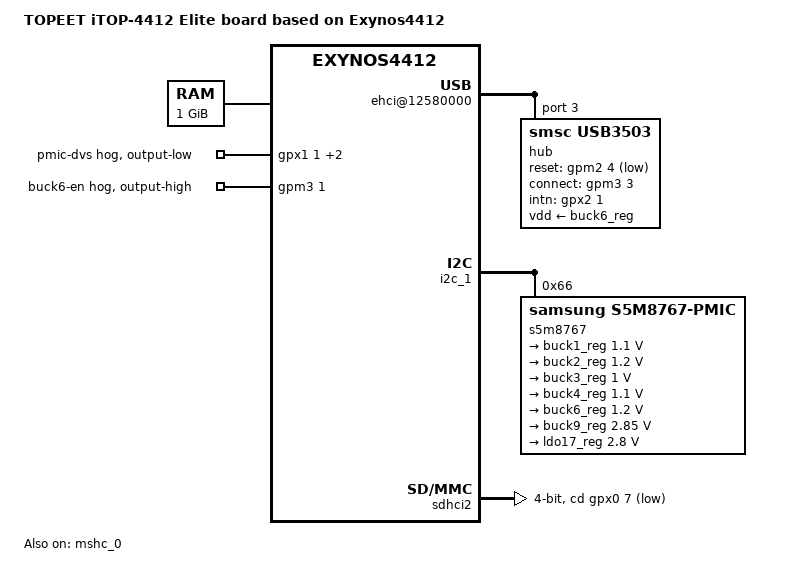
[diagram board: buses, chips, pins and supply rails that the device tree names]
/*
 * TOPEET's Exynos4412 based itop board device tree source
 *
 * Copyright (c) 2018 Samsung Electronics Co., Ltd.
 *		http://www.samsung.com
 *
 * SPDX-License-Identifier:	GPL-2.0+
 */

/dts-v1/;
#include <dt-bindings/gpio/gpio.h>
#include "skeleton.dtsi"
#include "exynos4412.dtsi"

/ {
	model = "TOPEET iTOP-4412 Elite board based on Exynos4412";
	compatible = "topeet,itop4412-elite", "samsung,exynos4412";

	chosen {
		bootargs ="console=ttySAC2,115200n8 androidboot.console=ttySAC2 ctp=1 skipcali=y";
	};

	config {
		bootcmd = "mmc rescan; mmc dev ${mmcbootdev}; \
			mmc read ${kernelloadaddr} ${kernelboff} ${kernelbsize}; \
			mmc read ${ramdiskloadaddr} ${ramdiskboff} ${ramdiskbsize}; \
			setenv initrd_high 0xffffffff; \
			bootz ${kernelloadaddr} ${ramdiskloadaddr}";
	};

	memory@40000000 {
		device_type = "memory";
		reg = <0x40000000 0x40000000>;
	};
	
	aliases {
		mmc0 = &mshc_0;
		mmc2 = &sdhci2;
		serial0 = "/serial@13820000";
		console = "/serial@13820000";
	};

	ehci@12580000 {
		compatible = "samsung,exynos-ehci";
		reg = <0x12580000 0x100>;
		#address-cells = <1>;
		#size-cells = <0>;
		status = "okay";
		/* In order to reset USB ethernet */
		samsung,vbus-gpio = <&gpc0 1 0>;

		phy {
			compatible = "samsung,exynos-usb-phy";
			reg = <0x125B0000 0x100>;
		};

		hub@3 {
			compatible = "smsc,usb3503";
			reg = <3>;
			vdd-supply = <&buck6_reg>;
			reset-gpios = <&gpm2 4 GPIO_ACTIVE_LOW>;
			connect-gpios = <&gpm3 3 GPIO_ACTIVE_HIGH>;
			intn-gpios = <&gpx2 1 GPIO_ACTIVE_HIGH>;
			initial-mode = <1>;
			refclk-frequency = <12000000>;
		};
	};

};

&gpx1 {
	pmic-dvs-hog {
		gpio-hog;
		gpios = <1 0>, <2 0>, <3 0>;
		output-low;
		line-name = "pmic-dvs";
	};
};

&gpm3 {
	buck6-en-hog {
		gpio-hog;
		gpios = <1 0>;
		output-high;
		line-name = "buck6-en";
	};
};

&i2c_1 {
	status = "okay";
	samsung,i2c-sda-delay = <100>;
	samsung,i2c-max-bus-freq = <400000>;

	s5m8767: pmic@66 {
		compatible = "samsung,s5m8767-pmic";
		reg = <0x66>;
		regulators {

			buck1_reg: BUCK1 {
				regulator-name = "VDD_MIF";
				regulator-min-microvolt = <1100000>;
				regulator-max-microvolt = <1100000>;
				regulator-always-on;
				regulator-boot-on;
			};

			buck2_reg: BUCK2 {
				regulator-name = "VDD_ARM";
				regulator-min-microvolt = <1200000>;
				regulator-max-microvolt = <1200000>;
				regulator-always-on;
				regulator-boot-on;
			};

			buck3_reg: BUCK3 {
				regulator-name = "VDD_INT";
				regulator-min-microvolt = <1000000>;
				regulator-max-microvolt = <1000000>;
				regulator-always-on;
				regulator-boot-on;
			};

			buck4_reg: BUCK4 {
				regulator-name = "VDD_G3D";
				regulator-min-microvolt = <1100000>;
				regulator-max-microvolt = <1100000>;
				regulator-always-on;
				regulator-boot-on;
			};

			buck6_reg: BUCK6 {
				regulator-name = "VDD12_5M_HUB";
				regulator-min-microvolt = <1200000>;
				regulator-max-microvolt = <1200000>;
				regulator-always-on;
				regulator-boot-on;
			};

			/* BUCK9, LDO17 for EMMC*/
			buck9_reg: BUCK9 {
				regulator-name = "VDDF28_EMMC";
				regulator-min-microvolt = <2850000>;
				regulator-max-microvolt = <2850000>;
				regulator-always-on;
				regulator-boot-on;
			};
			ldo17_reg: LDO17 {
				regulator-name = "VDDIOAP_MMC012_28";
				regulator-min-microvolt = <2800000>;
				regulator-max-microvolt = <2800000>;
				regulator-always-on;
				regulator-boot-on;
			};

		};
	};
};

&mshc_0 {
	div = <0x3>;
	index = <4>;
	samsung,dw-mshc-sdr-timing = <1 3>;
	bus-width = <8>;
	cap-mmc-highspeed;
	non-removable;
	broken-cd;
	card-detect-delay = <200>;
	vmmc-supply = <&buck9_reg>;
	vqmmc-supply = <&ldo17_reg>;
	status = "okay";
};

&sdhci2 {
	bus-width = <4>;
	samsung,timing = <1 2 3>;
	cd-gpios = <&gpx0 7 0>;
	cap-sd-highspeed;
	cd-inverted;
	status = "okay";
};
